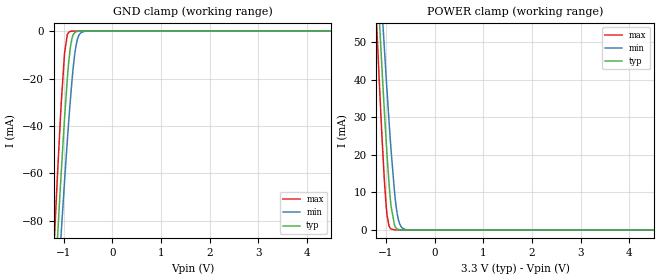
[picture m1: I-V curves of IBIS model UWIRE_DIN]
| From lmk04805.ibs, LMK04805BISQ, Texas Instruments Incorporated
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|   Model   UWIRE_DIN
[Model] UWIRE_DIN
Model_type Input
Vinl = 0.4V
Vinh = 1.6V
C_comp   0.1674p   0.1674pF   0.1674pF
[Voltage Range]   3.3   3.15   3.45
[Temperature Range]   45   125   -40
[Power Clamp Reference]   3.3   3.15   3.45
[GND Clamp Reference]   0   0   0
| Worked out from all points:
|   GND clamp passes 1 mA (typ) near -0.79 V on its own axis
|   POWER clamp passes 1 mA (typ) near -0.82 V on its own axis
[GND Clamp]
|   Voltage   I(typ)   I(min)   I(max)
-3.3V     -965.6mA   -893.6mA   -1.069A
-1.191V   -112.1mA   -132.7mA   -88.59mA
-1.117V   -84.4mA    -107.7mA   -57.4mA
-1.048V   -59.55mA   -84.92mA   -30.5mA
-978.5mV  -36.37mA   -62.95mA   -9.221mA
-924mV    -20.4mA    -46.56mA   -1.598mA
-859.7mV  -6.75mA    -28.81mA   -125.9uA
-795.3mV  -1.278mA   -14.16mA   -6.168uA
-735.9mV  -231.4uA   -5.307mA   -322.1nA
-681.5mV  -39.54uA   -1.674mA   -19.32nA
-577.5mV  -943.2nA   -148.2uA   0A
6.595V    0A         0A         0A
[POWER Clamp]
|   Voltage   I(typ)   I(min)   I(max)
-3.3V     638.8mA    590.5mA    708.3mA
-1.196V   70.39mA    83.75mA    55.37mA
-1.107V   48.47mA    63.9mA     30.8mA
-1.077V   41.42mA    57.43mA    23.19mA
-1.038V   32.31mA    48.95mA    13.93mA
-978.5mV  19.65mA    36.67mA    3.829mA
-899.2mV  6.493mA    21.57mA    264.8uA
-825mV    1.174mA    9.968mA    10.77uA
-765.6mV  254.2uA    3.922mA    572.9nA
-701.3mV  35.15uA    1.11mA     20.98nA
-582.5mV  494.5nA    81.77uA    0A
6.595V    0A         0A         0A
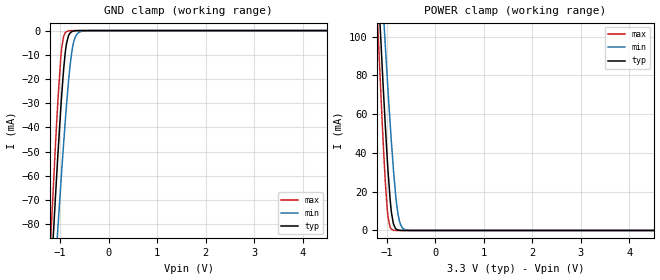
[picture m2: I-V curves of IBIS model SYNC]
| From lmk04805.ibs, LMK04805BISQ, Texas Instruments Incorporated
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|   Model SYNC
[Model]   SYNC
Model_type   Input
Vinl = 0.4
Vinh = 1.6
|   typ   min   max
|   (nom PVT)   (fast PVT)   (slow PVT)
C_comp   0.5966pF   0.57765pF   0.6104pF
[Voltage Range]   3.3   3.15   3.45
[Temperature Range]   27   125   -40
[Power Clamp Reference]   3.3   3.15   3.45
[GND Clamp Reference]   0   0   0
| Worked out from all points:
|   GND clamp passes 1 mA (typ) near -0.79 V on its own axis
|   POWER clamp passes 1 mA (typ) near -0.82 V on its own axis
[GND Clamp]
|   Voltage   I(typ)   I(min)   I(max)
-3.3V     -942.6mA   -854.7mA   -1.024A
-1.181V   -100.7mA   -125.5mA   -82.33mA
-1.092V   -68.4mA    -97.02mA   -46.97mA
-1.043V   -51.28mA   -81.58mA   -28.98mA
-963.6mV  -26.25mA   -57.73mA   -7.074mA
-924mV    -15.81mA   -46.4mA    -2.338mA
-864.6mV  -5.241mA   -30.59mA   -416.6uA
-785.4mV  -906.4uA   -13.39mA   -21.05uA
-726mV    -220.2uA   -5.463mA   -1.21uA
-656.7mV  -28.09uA   -1.707mA   0A
-537.9mV  -325.8nA   -217.8uA   0A
6.59V     0A         0A         0A
[POWER Clamp]
|   Voltage   I(typ)   I(min)   I(max)
-3.3V     1.303A     1.181A     1.417A
-1.191V   132mA      165.3mA    107.9mA
-1.181V   126.9mA    160.8mA    102.3mA
-1.092V   82.42mA    121.3mA    53.89mA
-1.063V   68.26mA    108.5mA    39.15mA
-993.3mV  37.62mA    79.36mA    11.46mA
-933.9mV  16.43mA    55.88mA    1.777mA
-864.6mV  3.384mA    31.47mA    134.7uA
-805.2mV  682.9uA    15.13mA    8.179uA
-745.8mV  107.4uA    5.402mA    0A
-577.5mV  0A         144uA      0A
6.59V     0A         0A         0A
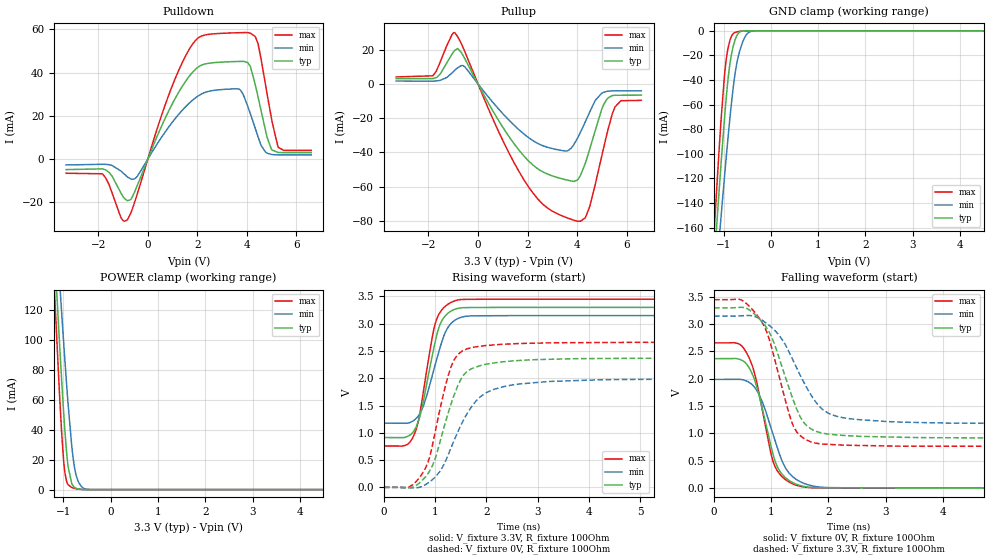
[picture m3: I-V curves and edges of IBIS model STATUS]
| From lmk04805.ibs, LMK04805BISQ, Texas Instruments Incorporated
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|   Model STATUS
[Model]   STATUS
Model_type   3-state
Polarity   Non-Inverting
Vmeas = 1.65
Vref = 3.3
Cref = 15pF
Rref = 100
|   typ   min   max
|   (nom PVT)   (Fast PVT)   (slow PVT)
C_comp   0.852p   0.826p   0.878p
|C_comp (ON state)   0.852p   0.826p   0.878p
|C_comp (Hi-Z state)   0.963p   0.892p   1.008p
| Where   nom PVT is  Nominal Process, 3.3V, 27C
|   Fast PVT is Strong Process, 3.45V, -40C
|   Slow PVT is Weak Process, 3.15V, 125C
[Voltage Range]   3.3   3.15   3.45
[Temperature Range]   45   125   -40
[Pullup Reference]   3.3   3.15   3.45
[Pulldown Reference]   0   0   0
[Power Clamp Reference]   3.3   3.15   3.45
[GND Clamp Reference]   0   0   0
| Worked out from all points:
|   slope of the pulldown table from 0 to 0.495 V, typ, clamps not added: 36.2 ohm
|   slope of the pullup table from 0 to 0.495 V, typ, clamps not added: 37.8 ohm
|   GND clamp passes 1 mA (typ) near -0.66 V on its own axis
|   POWER clamp passes 1 mA (typ) near -0.74 V on its own axis
|   falling waveform, V_fixture 0V, R_fixture 100Ohm: 20-80 % time 340ps typ, 395ps min, 319ps max; typ from 2.37 V to 0 V
|   rising waveform, V_fixture 3.3V, R_fixture 100Ohm: 20-80 % time 317ps typ, 363ps min, 289ps max; typ from 0.913 V to 3.3 V
|   rising waveform, V_fixture 0V, R_fixture 100Ohm: 20-80 % time 479ps typ, 648ps min, 398ps max; typ from 0 V to 2.37 V
|   falling waveform, V_fixture 3.3V, R_fixture 100Ohm: 20-80 % time 487ps typ, 615ps min, 431ps max; typ from 3.3 V to 0.913 V
[Pulldown]
|   Voltage   I(typ)   I(min)   I(max)
-3.3V     -4.892mA   -2.743mA   -6.588mA
-1.835V   -4.564mA   -2.442mA   -6.822mA
-825mV    -19.28mA   -8.265mA   -28.15mA
-458.7mV  -13.14mA   -8.471mA   -17.32mA
1.308V    32.1mA     21.52mA    42.6mA
1.947V    41.76mA    28.49mA    55.13mA
2.64V     44.53mA    31.7mA     57.87mA
3.749V    45.14mA    31.75mA    58.43mA
4.348V    33.78mA    13.78mA    56.36mA
4.823V    9.719mA    2.665mA    29.42mA
5.249V    3.056mA    1.88mA     5.834mA
6.595V    2.977mA    1.872mA    3.973mA
[GND Clamp]
|   Voltage   I(typ)   I(min)   I(max)
-3.3V     -1.445A    -1.261A    -1.617A
-1.191V   -184.5mA   -215.8mA   -158.4mA
-1.102V   -134.9mA   -174.1mA   -102.1mA
-1.068V   -116.1mA   -158.1mA   -81.43mA
-973.5mV  -68.37mA   -116mA     -33.62mA
-924mV    -46.56mA   -94.74mA   -18.18mA
-864.6mV  -26.51mA   -70.76mA   -7.701mA
-755.7mV  -7.442mA   -34.78mA   -1.352mA
-686.4mV  -1.941mA   -20.55mA   -642.8uA
-597.3mV  -190.5uA   -9.301mA   -163.9uA
-409.2mV  -1.365uA   -284.5uA   -1.421uA
6.595V    0A         0A         0A
[Pullup]
|   Voltage   I(typ)   I(min)   I(max)
-3.3V     3.006mA    1.669mA    4.028mA
-1.825V   3.027mA    1.569mA    4.69mA
-943.8mV  19.46mA    7.83mA     29.96mA
-547.8mV  15.12mA    10.13mA    19.39mA
838.2mV   -21.54mA   -14.77mA   -28.05mA
1.952V    -43.7mA    -30.41mA   -58.23mA
3.511V    -55.91mA   -39.24mA   -77.83mA
4.031V    -55.99mA   -31.39mA   -80.32mA
4.511V    -38.09mA   -16.47mA   -71.57mA
5.066V    -12.34mA   -4.976mA   -37.87mA
5.541V    -6.673mA   -4.126mA   -13.32mA
6.595V    -6.613mA   -4.081mA   -9.659mA
[POWER Clamp]
|   Voltage   I(typ)   I(min)   I(max)
-3.3V     1.514A     1.331A     1.68A
-1.186V   159.5mA    192.9mA    132.3mA
-1.073V   93.49mA    136.2mA    59.18mA
-1.038V   74.63mA    119.5mA    39.77mA
-988.3mV  49.52mA    96.26mA    17.72mA
-933.9mV  26.3mA     71.89mA    5.912mA
-899.2mV  15.56mA    57.33mA    3.324mA
-825mV    4.452mA    30.33mA    1.484mA
-770.5mV  1.699mA    16.33mA    941.9uA
-711.1mV  627.6uA    7.801mA    513.7uA
-508.2mV  14.36uA    214uA      13.03uA
6.595V    0A         0A         0A
[Ramp]
R_load = 100
|   typ   min   max
dV/dt_r   1.43198/3.16584e-10   1.18412/3.63204e-10   1.61487/2.88757e-10
dV/dt_f   1.42169/3.40249e-10   1.19281/3.94645e-10   1.5951/3.18511e-10
[Falling Waveform]
V_fixture = 0V
V_fixture_min = 0V
V_fixture_max = 0V
R_fixture = 100Ohm
C_fixture = 0F
|   Time   V(typ)   V(min)   V(max)
0s        2.369V     1.988V     2.658V
403.5ps   2.368V     1.989V     2.65V
559.4ps   2.279V     1.962V     2.493V
680.4ps   2.055V     1.877V     2.201V
774.4ps   1.748V     1.739V     1.792V
1.052ns   539mV      910.8mV    422.6mV
1.254ns   180.9mV    354.3mV    145.6mV
1.488ns   47.87mV    122.7mV    33.51mV
2.252ns   1.601mV    1.845mV    1.544mV
10ns      -430.4nV   766.5nV    -1.085uV
[Rising Waveform]
V_fixture = 3.3V
V_fixture_min = 3.15V
V_fixture_max = 3.45V
R_fixture = 100Ohm
C_fixture = 0F
|   Time   V(typ)   V(min)   V(max)
0s        913.4mV    1.176V     758.5mV
403.5ps   915.4mV    1.175V     766.5mV
559.4ps   1.004V     1.213V     904.2mV
694.3ps   1.275V     1.343V     1.327V
774.4ps   1.606V     1.502V     1.784V
1.003ns   2.681V     2.259V     3.009V
1.137ns   3.067V     2.691V     3.262V
1.254ns   3.195V     2.941V     3.36V
1.389ns   3.265V     3.066V     3.422V
10ns      3.3V       3.15V      3.45V
[Rising Waveform]
V_fixture = 0V
V_fixture_min = 0V
V_fixture_max = 0V
R_fixture = 100Ohm
C_fixture = 0F
|   Time   V(typ)   V(min)   V(max)
0s        818.8pV    7.568nV    788.8pV
477.3ps   -7.987mV   -4.166mV   1.593mV
738.5ps   122.8mV    15.84mV    236.7mV
863.5ps   260.1mV    83.14mV    473mV
997.7ps   521.5mV    188mV      1.007V
1.312ns   1.537V     731.4mV    2.218V
1.628ns   2.127V     1.362V     2.541V
2.147ns   2.281V     1.797V     2.611V
3.22ns    2.347V     1.941V     2.648V
10ns      2.369V     1.988V     2.658V
[Falling Waveform]
|Gnd
V_fixture = 3.3V
V_fixture_min = 3.15V
V_fixture_max = 3.45V
R_fixture = 100Ohm
C_fixture = 0F
|   Time   V(typ)   V(min)   V(max)
0s        3.3V       3.15V      3.45V
477.3ps   3.31V      3.155V     3.447V
812ps     3.075V     3.091V     3.079V
1.023ns   2.725V     2.926V     2.505V
1.389ns   1.599V     2.319V     1.125V
1.553ns   1.219V     1.968V     918.7mV
1.756ns   1.05V      1.606V     824.2mV
2.147ns   970.5mV    1.31V      789.2mV
3.02ns    933.8mV    1.216V     768.6mV
10ns      913.4mV    1.176V     758.6mV
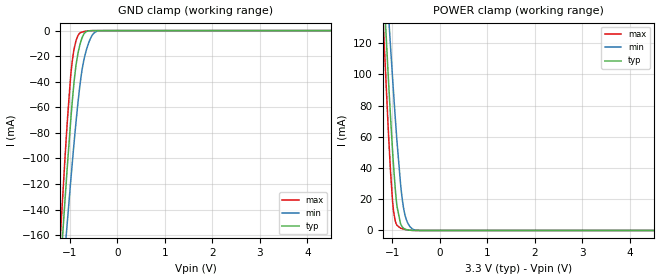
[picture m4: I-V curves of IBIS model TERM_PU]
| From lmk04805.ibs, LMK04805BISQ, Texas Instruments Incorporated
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|   Model TERM_PU
[Model]   TERM_PU
Model_type   Terminator
|   typ   min   max
|   (nom PVT)   (Fast PVT)   (slow PVT)
C_comp   0.963p   0.892p   1.008p
[Voltage Range]   3.3   3.15   3.45
[Temperature Range]   45   125   -40
[Power Clamp Reference]   3.3   3.15   3.45
[GND Clamp Reference]   0   0   0
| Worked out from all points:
|   GND clamp passes 1 mA (typ) near -0.66 V on its own axis
|   POWER clamp passes 1 mA (typ) near -0.74 V on its own axis
[GND Clamp]
|   Voltage   I(typ)   I(min)   I(max)
-3.3V     -1.445A    -1.261A    -1.617A
-1.191V   -184.5mA   -215.8mA   -158.4mA
-1.102V   -134.9mA   -174.1mA   -102.1mA
-1.068V   -116.1mA   -158.1mA   -81.44mA
-973.5mV  -68.37mA   -116mA     -33.63mA
-924mV    -46.56mA   -94.74mA   -18.19mA
-864.6mV  -26.51mA   -70.76mA   -7.714mA
-755.7mV  -7.45mA    -34.78mA   -1.369mA
-686.4mV  -1.952mA   -20.55mA   -660.6uA
-597.3mV  -204.1uA   -9.306mA   -182.9uA
-409.2mV  -15.71uA   -293.6uA   -21.26uA
6.595V    0A         0A         0A
[POWER Clamp]
|   Voltage   I(typ)   I(min)   I(max)
-3.3V     1.514A     1.331A     1.68A
-1.186V   159.5mA    192.9mA    132.3mA
-1.073V   93.49mA    136.2mA    59.19mA
-1.038V   74.63mA    119.5mA    39.77mA
-988.3mV  49.53mA    96.26mA    17.72mA
-933.9mV  26.3mA     71.89mA    5.924mA
-899.2mV  15.57mA    57.34mA    3.337mA
-825mV    4.459mA    30.33mA    1.498mA
-765.6mV  1.564mA    15.37mA    914.2uA
-706.2mV  591.9uA    7.339mA    497.5uA
-503.2mV  20.75uA    194.8uA    21.71uA
6.595V    0A         0A         0A
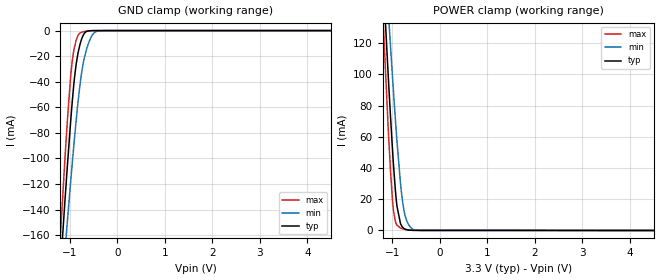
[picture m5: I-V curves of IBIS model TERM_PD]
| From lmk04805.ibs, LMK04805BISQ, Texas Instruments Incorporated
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|   Model TERM_PD
[Model]   TERM_PD
Model_type   Terminator
|   typ   min   max
|   (nom PVT)   (Fast PVT)   (slow PVT)
C_comp   0.963p   0.892p   1.008p
[Voltage Range]   3.3   3.15   3.45
[Temperature Range]   45   125   -40
[Power Clamp Reference]   3.3   3.15   3.45
[GND Clamp Reference]   0   0   0
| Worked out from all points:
|   GND clamp passes 1 mA (typ) near -0.66 V on its own axis
|   POWER clamp passes 1 mA (typ) near -0.74 V on its own axis
[GND Clamp]
|   Voltage   I(typ)   I(min)   I(max)
-3.3V     -1.445A    -1.261A    -1.617A
-1.191V   -184.6mA   -215.8mA   -158.4mA
-1.102V   -134.9mA   -174.1mA   -102.1mA
-1.068V   -116.1mA   -158.1mA   -81.45mA
-973.5mV  -68.37mA   -116mA     -33.64mA
-924mV    -46.57mA   -94.75mA   -18.2mA
-864.6mV  -26.52mA   -70.76mA   -7.729mA
-755.7mV  -7.458mA   -34.78mA   -1.386mA
-686.4mV  -1.961mA   -20.55mA   -675.4uA
-597.3mV  -211.8uA   -9.308mA   -194.7uA
-409.2mV  -16.79uA   -293.4uA   -23.76uA
6.595V    0A         0A         0A
[POWER Clamp]
|   Voltage   I(typ)   I(min)   I(max)
-3.3V     1.514A     1.331A     1.68A
-1.186V   159.5mA    192.9mA    132.3mA
-1.073V   93.5mA     136.2mA    59.2mA
-1.038V   74.63mA    119.5mA    39.78mA
-988.3mV  49.53mA    96.26mA    17.74mA
-933.9mV  26.31mA    71.89mA    5.959mA
-899.2mV  15.58mA    57.34mA    3.379mA
-825mV    4.476mA    30.33mA    1.546mA
-770.5mV  1.732mA    16.33mA    1.005mA
-711.1mV  666.7uA    7.809mA    578.9uA
-508.2mV  58.14uA    237.1uA    83.59uA
6.595V    0A         0A         0A
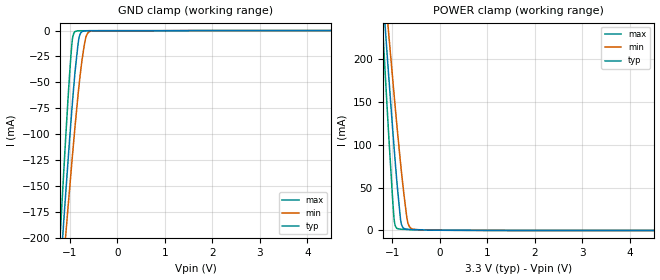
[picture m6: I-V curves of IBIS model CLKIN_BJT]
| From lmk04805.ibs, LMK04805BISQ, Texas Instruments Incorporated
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|   Model   CLKIN_BJT
[Model]   CLKIN_BJT
Model_type   Input
Vinl = 1.7125
Vinh = 1.8875
|   typ   min   max
|   (nom PVT)   (fast PVT)   (slow PVT)
C_comp   0.5966pF   0.57765pF   0.6104pF
[Voltage Range]   3.3   3.15   3.45
[Temperature Range]   45   125   -40
[Power Clamp Reference]   3.3   3.15   3.45
[GND Clamp Reference]   0   0   0
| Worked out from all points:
|   GND clamp passes 1 mA (typ) near -0.74 V on its own axis
|   POWER clamp passes 1 mA (typ) near -0.56 V on its own axis
[GND Clamp]
|   Voltage   I(typ)   I(min)   I(max)
-3.3V     -1.673A    -1.493A    -1.972A
-1.221V   -248.3mA   -275.9mA   -215.2mA
-1.102V   -169.7mA   -208.7mA   -118.3mA
-1.073V   -150.4mA   -192.1mA   -94.94mA
-1.003V   -106.5mA   -154mA     -43.49mA
-953.7mV  -76.5mA    -127.3mA   -13.15mA
-884.4mV  -38.7mA    -91.36mA   -857.5uA
-805.2mV  -7.498mA   -53.9mA    -165.3uA
-696.3mV  -342.3uA   -15.33mA   -143.2uA
-646.8mV  -172.4uA   -4.808mA   -141uA
-557.7mV  -135.8uA   -573uA     -137.4uA
6.59V     0A         0A         0A
[POWER Clamp]
|   Voltage   I(typ)   I(min)   I(max)
-3.3V     1.955A     1.71A      2.384A
-1.231V   302.5mA    331.3mA    267.3mA
-1.112V   210.5mA    254.7mA    149.5mA
-1.082V   187.8mA    235.7mA    120.7mA
-963.6mV  99.58mA    161mA      15.8mA
-933.9mV  78.8mA     142.7mA    5.4mA
-894.3mV  52.62mA    118.9mA    2.255mA
-825mV    13.12mA    79.23mA    1.5mA
-795.3mV  5.734mA    63.42mA    1.417mA
-676.5mV  1.302mA    10.59mA    1.157mA
-567.6mV  1.023mA    1.567mA    928.8uA
6.59V     0A         0A         0A
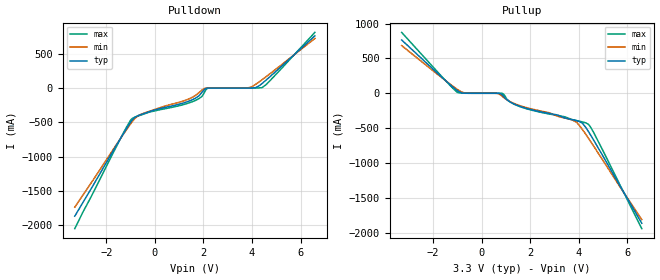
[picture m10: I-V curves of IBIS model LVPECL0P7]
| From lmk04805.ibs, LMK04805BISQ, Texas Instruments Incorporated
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|   Model LVPECL0P7V
[Model]   LVPECL0P7
Model_type   Output
Polarity   Non-Inverting
Vmeas = 2.25
Vref = 1.99
Cref = .3pF
Rref = 240
|   typ   min   max
|   (nom PVT)   (fast PVT)   (slow PVT)
C_comp   0.2109p   0.1807p   0.2310p
|C_comp (Low state)   0.2109p   0.1807p   0.2310p
|C_comp (High state)   0.9933p   0.9197p   1.0724p
[Voltage Range]   3.3   3.15   3.45
[Temperature Range]   45   125   -40
[Pullup Reference]   3.3   3.15   3.45
[Pulldown Reference]   0   0   0
[Power Clamp Reference]   3.3   3.15   3.45
[GND Clamp Reference]   0   0   0
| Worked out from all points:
|   slope of the pulldown table from 0 to 0.495 V, typ, clamps not added: 11.7 ohm
[Pulldown]
|   Voltage   I(typ)   I(min)   I(max)
-3.3V     -1.868A    -1.737A    -2.051A
-1.33V    -684.9mA   -690mA     -677.1mA
-924mV    -461.3mA   -486.2mA   -440.9mA
-547.8mV  -384.3mA   -379.7mA   -391mA
1.571V    -166.7mA   -129.5mA   -195.8mA
1.917V    -73.32mA   -36.85mA   -128.6mA
2.185V    -456.4uA   -209.6uA   -1.656mA
3.887V    106.5uA    6.161mA    2.469uA
4.155V    6.485mA    54.36mA    475.7uA
4.412V    65.2mA     120mA      6.277mA
4.877V    208.6mA    245.8mA    157.5mA
6.59V     761.2mA    723.2mA    811.3mA
[Pullup]
|   Voltage   I(typ)   I(min)   I(max)
-3.3V     764.4mA    683.9mA    873mA
-983.4mV  30.09mA    49.29mA    9.236mA
-686.4mV  508.5uA    3.353mA    377.6uA
561mV     -3.207uA   -265.7uA   -15.17nA
848.1mV   -23.45mA   -44.55mA   -1.601mA
1.115V    -113.4mA   -110.1mA   -110.4mA
1.531V    -182.8mA   -172.9mA   -185.6mA
3.719V    -377.8mA   -382.8mA   -377.4mA
4.125V    -425.1mA   -509.2mA   -408.9mA
4.392V    -547.4mA   -644mA     -445mA
5.046V    -932.9mA   -991.5mA   -859.3mA
6.59V     -1.864A    -1.812A    -1.942A
[Ramp]
R_load = 240
|   typ   min   max
dV/dt_r   0.244219/5.04729e-11   0.241494/5.98561e-11   0.246578/4.31865e-11
dV/dt_f   0.244239/4.18475e-11   0.241516/5.25506e-11   0.246591/3.29896e-11
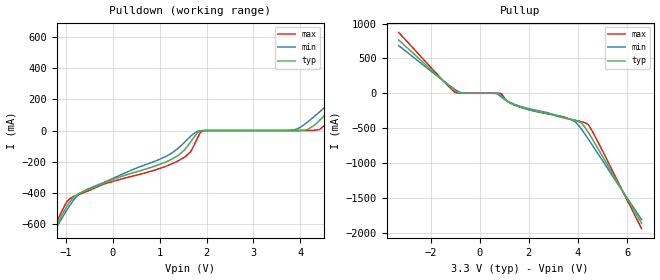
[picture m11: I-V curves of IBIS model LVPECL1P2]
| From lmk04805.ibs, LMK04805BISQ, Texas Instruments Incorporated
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|   Model LVPECL1P2V
[Model]   LVPECL1P2
Model_type   Output
Polarity   Non-Inverting
Vmeas = 2.15
Vref = 1.99
Cref = .3pF
Rref = 240
|   typ   min   max
|   (nom PVT)   (fast PVT)   (slow PVT)
C_comp   0.2109p   0.1807p   0.2310p
|C_comp (Low state)   0.2109p   0.1807p   0.2310p
|C_comp (High state)   0.9933p   0.9197p   1.0724p
[Voltage Range]   3.3   3.15   3.45
[Temperature Range]   45   125   -40
[Pullup Reference]   3.3   3.15   3.45
[Pulldown Reference]   0   0   0
[Power Clamp Reference]   3.3   3.15   3.45
[GND Clamp Reference]   0   0   0
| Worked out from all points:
|   slope of the pulldown table from 0 to 0.495 V, typ, clamps not added: 10.3 ohm
[Pulldown]
|   Voltage   I(typ)   I(min)   I(max)
-3.3V     -1.869A    -1.737A    -2.051A
-1.31V    -672.1mA   -678.7mA   -662.3mA
-924mV    -459.7mA   -484.6mA   -439.3mA
-547.8mV  -383.2mA   -378.2mA   -390.1mA
1.383V    -162mA     -116.7mA   -196.5mA
1.65V     -77.31mA   -39.98mA   -139.3mA
1.917V    -604.4uA   -272.6uA   -2.275mA
3.887V    106.5uA    6.161mA    2.469uA
4.155V    6.485mA    54.36mA    475.7uA
4.412V    65.2mA     120mA      6.277mA
5.145V    293.7mA    319.5mA    257.9mA
6.59V     761.2mA    723.2mA    811.3mA
[Pullup]
|   Voltage   I(typ)   I(min)   I(max)
-3.3V     764.4mA    683.9mA    873mA
-983.4mV  30.09mA    49.29mA    9.236mA
-686.4mV  508.5uA    3.353mA    377.6uA
561mV     -3.204uA   -264.7uA   -15.17nA
848.1mV   -23.44mA   -44.51mA   -1.601mA
1.115V    -113.4mA   -110mA     -110.4mA
1.531V    -182.8mA   -172.9mA   -185.6mA
3.679V    -372.4mA   -375.7mA   -372.1mA
4.125V    -423.4mA   -507.7mA   -407mA
4.392V    -545.9mA   -642.8mA   -443.4mA
5.016V    -914.6mA   -975.5mA   -837.7mA
6.59V     -1.865A    -1.812A    -1.942A
[Ramp]
R_load = 240
|   typ   min   max
dV/dt_r   0.39645/4.95323e-11   0.391812/5.93959e-11   0.400409/4.21824e-11
dV/dt_f   0.396487/4.52165e-11   0.391853/5.46431e-11   0.400432/3.73452e-11
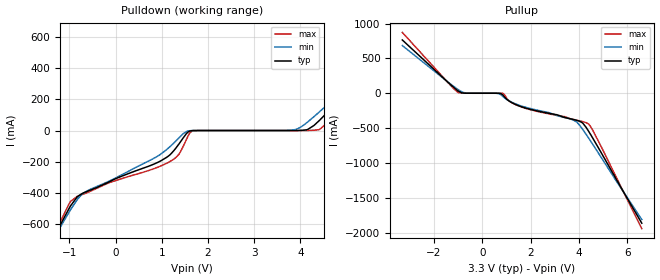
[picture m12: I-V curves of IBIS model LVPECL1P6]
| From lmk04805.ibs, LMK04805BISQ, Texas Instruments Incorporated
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|   Model LVPECL1P6V
[Model]   LVPECL1P6
Model_type   Output
Polarity   Non-Inverting
Vmeas = 2.05
Vref = 1.99
Cref = .3pF
Rref = 240
|   typ   min   max
|   (nom PVT)   (fast PVT)   (slow PVT)
C_comp   0.2109p   0.1807p   0.2310p
|C_comp (Low state)   0.2109p   0.1807p   0.2310p
|C_comp (High state)   0.9933p   0.9197p   1.0724p
[Voltage Range]   3.3   3.15   3.45
[Temperature Range]   45   125   -40
[Pullup Reference]   3.3   3.15   3.45
[Pulldown Reference]   0   0   0
[Power Clamp Reference]   3.3   3.15   3.45
[GND Clamp Reference]   0   0   0
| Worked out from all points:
|   slope of the pulldown table from 0 to 0.495 V, typ, clamps not added: 8.73 ohm
[Pulldown]
|   Voltage   I(typ)   I(min)   I(max)
-3.3V     -1.869A    -1.737A    -2.051A
-1.29V    -659.3mA   -667.3mA   -647.5mA
-1.003V   -497mA     -520.8mA   -467.3mA
-825mV    -422.7mA   -440mA     -420.4mA
1.175V    -155.7mA   -103.7mA   -198.5mA
1.373V    -85.35mA   -46.2mA    -151.1mA
1.66V     -569.6uA   -270.8uA   -2.008mA
3.887V    106.5uA    6.161mA    2.469uA
4.155V    6.485mA    54.36mA    475.7uA
4.412V    65.2mA     120mA      6.277mA
5.145V    293.7mA    319.5mA    257.9mA
6.59V     761.2mA    723.2mA    811.3mA
[Pullup]
|   Voltage   I(typ)   I(min)   I(max)
-3.3V     764.4mA    683.9mA    873mA
-983.4mV  30.09mA    49.29mA    9.236mA
-686.4mV  508.5uA    3.353mA    377.6uA
561mV     -3.199uA   -263.1uA   -15.17nA
848.1mV   -23.43mA   -44.45mA   -1.6mA
1.115V    -113.4mA   -110mA     -110.4mA
1.531V    -182.7mA   -172.9mA   -185.6mA
3.739V    -374.5mA   -381.3mA   -374.9mA
4.125V    -421.7mA   -506.1mA   -405.1mA
4.392V    -544.4mA   -641.7mA   -441.8mA
4.986V    -896.2mA   -959.4mA   -816.1mA
6.59V     -1.865A    -1.813A    -1.943A
[Ramp]
R_load = 240
|   typ   min   max
dV/dt_r   0.548292/4.99905e-11   0.541543/6.09757e-11   0.55397/4.17605e-11
dV/dt_f   0.548346/5.2725e-11   0.5416/6.22718e-11   0.553999/4.51898e-11
